VERSION 5.8 ;
BUSBITCHARS "[]" ;
DIVIDERCHAR "/" ;
UNITS
    DATABASE MICRONS 1000 ;
END UNITS

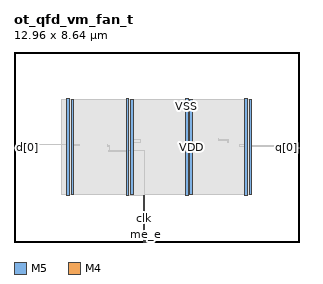
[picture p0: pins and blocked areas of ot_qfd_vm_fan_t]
MACRO ot_qfd_vm_fan_t
  FOREIGN ot_qfd_vm_fan_t 0 0 ;
  CLASS BLOCK ;
  SIZE 12.96 BY 8.64 ;
  PIN clk
    DIRECTION INPUT ;
    USE SIGNAL ;
    PORT
      LAYER M5 ;
        RECT  5.904 0 5.928 0.084 ;
    END
    PORT
      LAYER M5 ;
        RECT  5.904 0.016 5.928 2.137 ;
    END
  END clk
  PIN d[0]
    DIRECTION INPUT ;
    USE SIGNAL ;
    PORT
      LAYER M4 ;
        RECT  0 4.272 0.084 4.296 ;
    END
    PORT
      LAYER M4 ;
        RECT  0.06 4.272 0.097 4.296 ;
    END
  END d[0]
  PIN me_e
    DIRECTION INPUT ;
    USE SIGNAL ;
    PORT
      LAYER M5 ;
        RECT  6 0 6.024 0.084 ;
    END
  END me_e
  PIN q[0]
    DIRECTION OUTPUT ;
    USE SIGNAL ;
    PORT
      LAYER M4 ;
        RECT  12.876 4.272 12.96 4.296 ;
    END
    PORT
      LAYER M4 ;
        RECT  11.886 4.272 12.924 4.296 ;
    END
  END q[0]
  PIN VDD
    DIRECTION INOUT ;
    USE POWER ;
    PORT
      LAYER M5 ;
        RECT  10.692 2.151 10.812 6.489 ;
        RECT  7.992 2.151 8.112 6.489 ;
        RECT  5.292 2.151 5.412 6.489 ;
        RECT  2.592 2.151 2.712 6.489 ;
    END
  END VDD
  PIN VSS
    DIRECTION INOUT ;
    USE GROUND ;
    PORT
      LAYER M5 ;
        RECT  10.5 2.137 10.62 6.503 ;
        RECT  7.8 2.137 7.92 6.503 ;
        RECT  5.1 2.137 5.22 6.503 ;
        RECT  2.4 2.137 2.52 6.503 ;
    END
  END VSS
  # OT_OBS_CLOSED layer=M5 d_um=1.536 added=0
  OBS
    LAYER RVTN ;
     RECT  2.16 2.16 10.8 2.295 ;
     RECT  2.16 2.565 10.8 2.835 ;
     RECT  2.16 3.105 10.8 3.375 ;
     RECT  2.16 3.645 10.8 3.915 ;
     RECT  2.16 4.185 10.8 4.455 ;
     RECT  2.16 4.725 10.8 4.995 ;
     RECT  2.16 5.265 10.8 5.535 ;
     RECT  2.16 5.805 10.8 6.075 ;
     RECT  2.16 6.345 10.8 6.48 ;
    LAYER RVTP ;
     RECT  2.16 2.295 10.8 2.565 ;
     RECT  2.16 2.835 10.8 3.105 ;
     RECT  2.16 3.375 10.8 3.645 ;
     RECT  2.16 3.915 10.8 4.185 ;
     RECT  2.16 4.455 10.8 4.725 ;
     RECT  2.16 4.995 10.8 5.265 ;
     RECT  2.16 5.535 10.8 5.805 ;
     RECT  2.16 6.075 10.8 6.345 ;
    LAYER M1 ;
     RECT  2.16 2.151 10.8 6.489 ;
    LAYER M2 ;
     RECT  2.16 2.151 10.8 6.489 ;
     RECT  10.8 2.421 10.812 6.219 ;
     RECT  10.812 4.356 11.975 4.374 ;
    LAYER M3 ;
     RECT  2.415 2.143 2.505 2.413 ;
     RECT  5.115 2.143 5.205 2.413 ;
     RECT  7.815 2.143 7.905 2.413 ;
     RECT  10.515 2.143 10.605 2.413 ;
     RECT  4.32 4.123 4.338 4.351 ;
     RECT  10.515 2.413 10.797 4.351 ;
     RECT  4.248 4.351 4.338 4.379 ;
     RECT  11.952 4.267 11.97 4.379 ;
     RECT  2.415 2.413 2.697 4.387 ;
     RECT  0.108 4.267 0.126 4.445 ;
     RECT  2.415 4.387 2.97 4.445 ;
     RECT  4.248 4.379 4.266 4.451 ;
     RECT  10.26 4.351 10.797 4.451 ;
     RECT  5.115 2.413 5.397 4.531 ;
     RECT  9.72 4.531 9.738 4.621 ;
     RECT  5.115 4.531 5.742 4.649 ;
     RECT  9.288 4.621 9.738 4.649 ;
     RECT  9.288 4.649 9.306 4.721 ;
     RECT  2.415 4.445 2.697 6.227 ;
     RECT  5.115 4.649 5.397 6.227 ;
     RECT  7.815 2.413 8.097 6.227 ;
     RECT  10.515 4.451 10.797 6.227 ;
     RECT  2.415 6.227 2.505 6.497 ;
     RECT  5.115 6.227 5.205 6.497 ;
     RECT  7.815 6.227 7.905 6.497 ;
     RECT  10.515 6.227 10.605 6.497 ;
    LAYER M4 ;
     RECT  0.097 4.272 0.137 4.44 ;
     RECT  0.137 4.416 2.408 4.44 ;
     RECT  2.408 2.148 2.512 6.492 ;
     RECT  2.512 2.418 2.704 6.222 ;
     RECT  2.704 4.416 2.981 4.44 ;
     RECT  4.309 4.128 5.108 4.152 ;
     RECT  5.108 2.148 5.212 6.492 ;
     RECT  5.212 2.418 5.404 6.222 ;
     RECT  5.404 4.128 5.939 4.152 ;
     RECT  7.808 2.148 7.912 6.492 ;
     RECT  7.912 2.418 8.104 6.222 ;
     RECT  10.508 2.148 10.612 6.492 ;
     RECT  10.612 2.418 10.804 6.222 ;
    LAYER M5 ;
     RECT  2.4 2.137 2.52 2.151 ;
     RECT  7.8 2.137 7.92 2.151 ;
     RECT  10.5 2.137 10.62 2.151 ;
     RECT  5.1 2.137 5.928 4.163 ;
     RECT  2.4 2.151 2.712 6.489 ;
     RECT  5.1 4.163 5.412 6.489 ;
     RECT  7.8 2.151 8.112 6.489 ;
     RECT  10.5 2.151 10.812 6.489 ;
     RECT  2.4 6.489 2.52 6.503 ;
     RECT  5.1 6.489 5.22 6.503 ;
     RECT  7.8 6.489 7.92 6.503 ;
     RECT  10.5 6.489 10.62 6.503 ;
  END
END ot_qfd_vm_fan_t
END LIBRARY
